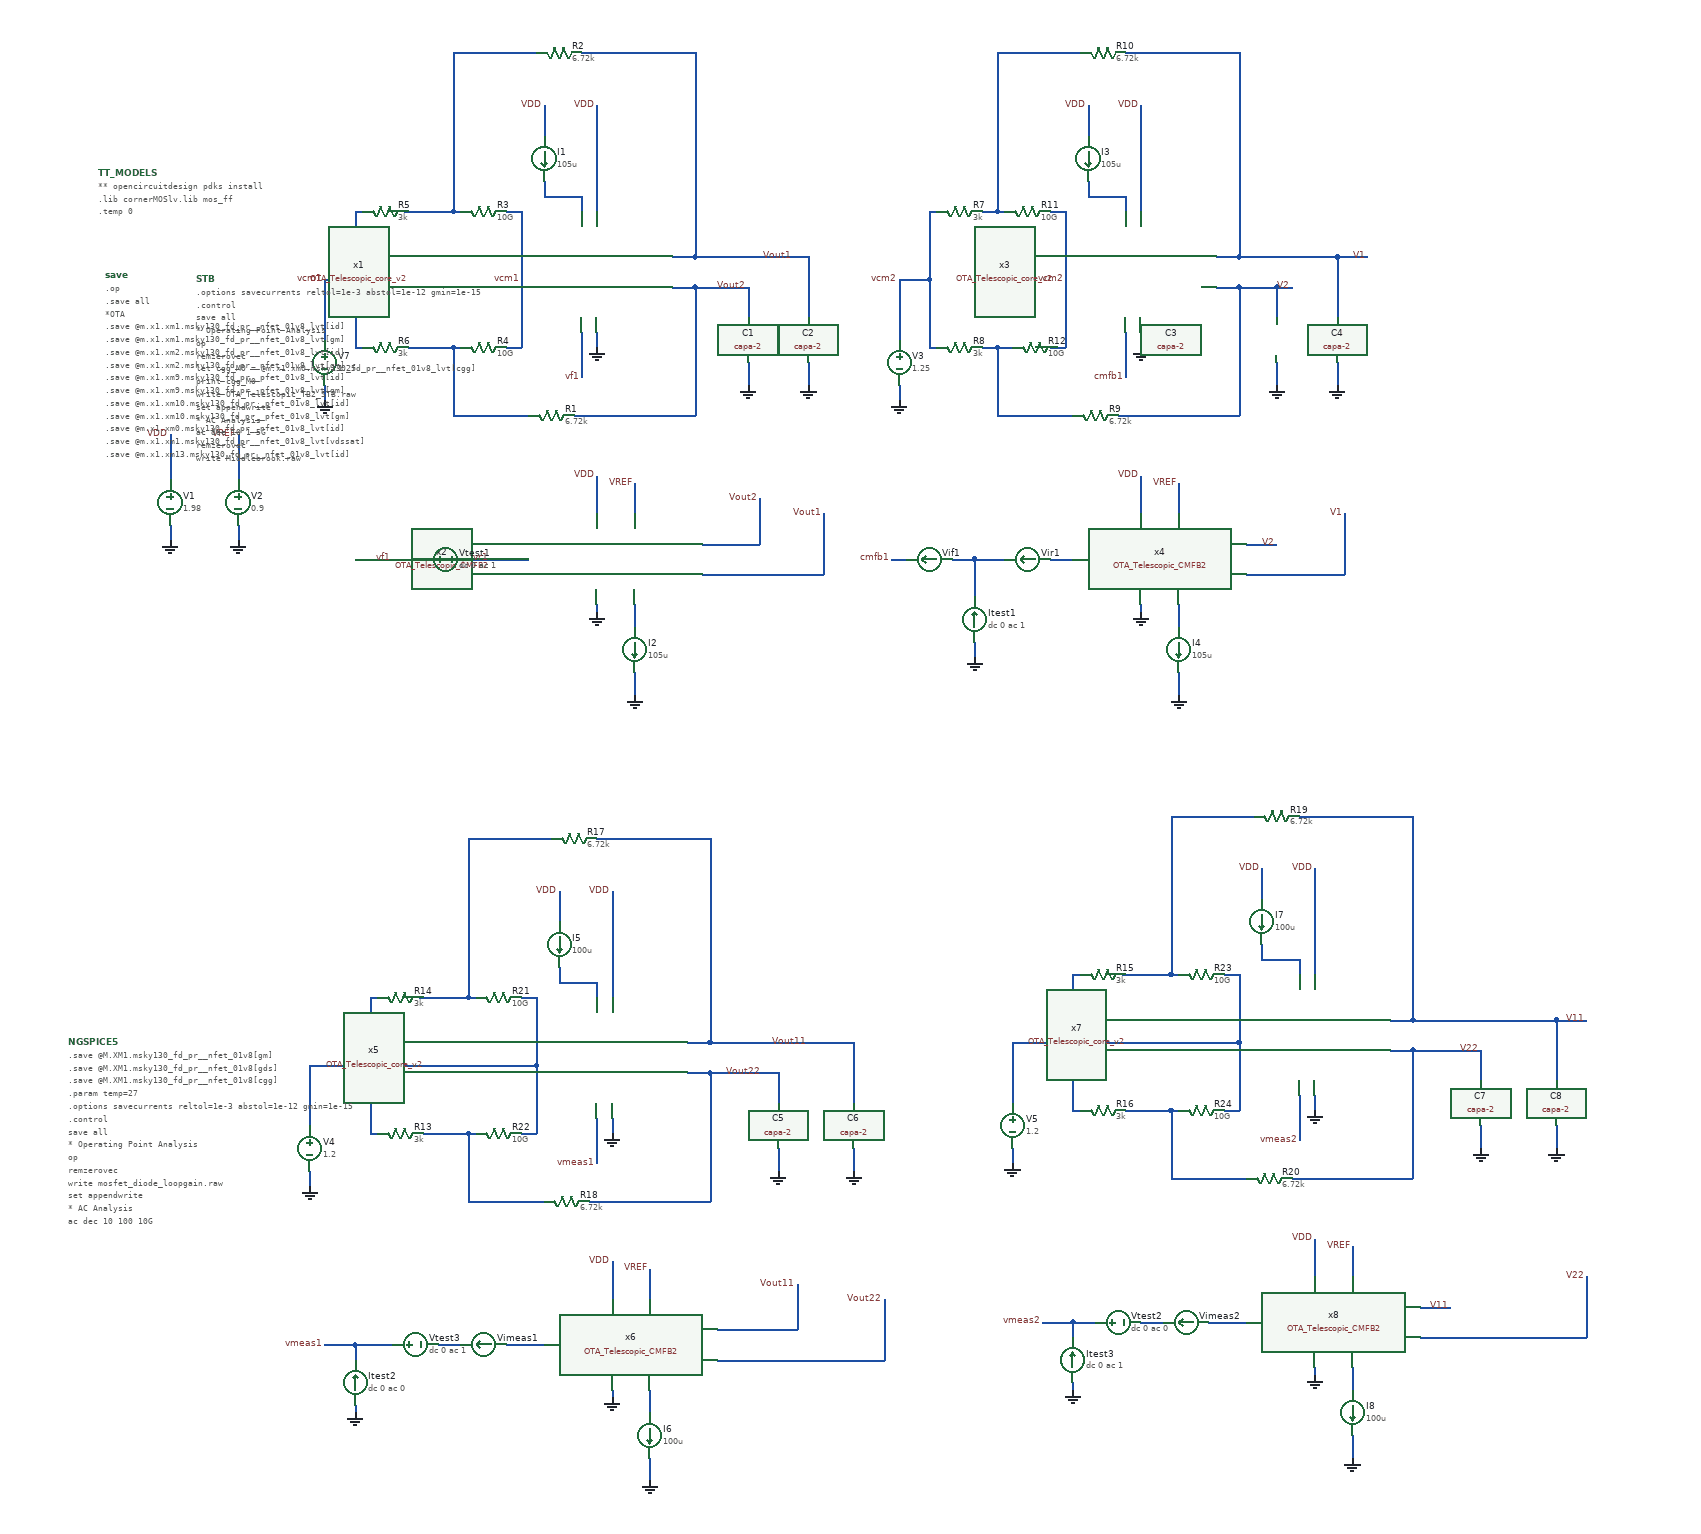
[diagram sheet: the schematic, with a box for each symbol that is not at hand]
v {xschem version=3.4.8RC file_version=1.2}
G {}
K {}
V {}
S {}
F {}
E {}
N 220 -440 370 -440 {lab=Vout1}
N -270 -410 -270 -330 {lab=vcm1}
N -270 -270 -270 -250 {lab=GND}
N 90 -340 90 -320 {lab=GND}
N -475 -85 -475 -65 {lab=GND}
N -475 -205 -475 -145 {lab=VDD}
N -385 -85 -385 -65 {lab=GND}
N -385 -205 -385 -145 {lab=VREF}
N 290 -400 290 -360 {lab=Vout2}
N 290 -300 290 -270 {lab=GND}
N 370 -300 370 -270 {lab=GND}
N 370 -440 370 -360 {lab=Vout1}
N -10 -500 -10 -320 {lab=vcm1}
N 70 -340 70 -280 {lab=vf1}
N 305 -120 305 -60 {lab=Vout2}
N -30 -500 -10 -500 {lab=vcm1}
N -30 -320 -10 -320 {lab=vcm1}
N -100 -500 -90 -500 {lab=#net1}
N -100 -320 -90 -320 {lab=#net2}
N 90 -640 90 -500 {lab=VDD}
N 20 -540 20 -520 {lab=#net3}
N 20 -520 70 -520 {lab=#net3}
N 70 -520 70 -500 {lab=#net3}
N 20 -640 20 -600 {lab=VDD}
N 190 -400 220 -400 {lab=Vout2}
N 140 -140 140 -100 {lab=VREF}
N 90 20 90 30 {lab=GND}
N 140 110 140 140 {lab=GND}
N 140 20 140 50 {lab=#net4}
N 90 -150 90 -100 {lab=VDD}
N -100 -710 10 -710 {lab=#net1}
N -100 -710 -100 -500 {lab=#net1}
N 70 -710 220 -710 {lab=Vout1}
N 220 -710 220 -440 {lab=Vout1}
N -100 -320 -100 -230 {lab=#net2}
N -100 -230 0 -230 {lab=#net2}
N 60 -230 220 -230 {lab=Vout2}
N 220 -400 220 -230 {lab=Vout2}
N 230 -20 390 -20 {lab=Vout1}
N -230 -320 -220 -320 {lab=vcm1}
N -230 -410 -230 -320 {lab=vcm1}
N -230 -500 -220 -500 {lab=vcm1}
N 390 -100 390 -20 {lab=Vout1}
N 490 -410 490 -330 {lab=vcm2}
N 490 -270 490 -250 {lab=GND}
N 810 -340 810 -320 {lab=GND}
N 990 -400 990 -360 {lab=V2}
N 990 -300 990 -270 {lab=GND}
N 1070 -300 1070 -270 {lab=GND}
N 1070 -440 1070 -360 {lab=V1}
N 710 -500 710 -320 {lab=vcm2}
N 790 -340 790 -280 {lab=cmfb1}
N 690 -500 710 -500 {lab=vcm2}
N 690 -320 710 -320 {lab=vcm2}
N 810 -640 810 -500 {lab=VDD}
N 740 -540 740 -520 {lab=#net5}
N 740 -520 790 -520 {lab=#net5}
N 790 -520 790 -500 {lab=#net5}
N 740 -640 740 -600 {lab=VDD}
N 910 -400 940 -400 {lab=V2}
N 860 -140 860 -100 {lab=VREF}
N 810 20 810 30 {lab=GND}
N 860 110 860 140 {lab=GND}
N 860 20 860 50 {lab=#net6}
N 810 -150 810 -100 {lab=VDD}
N 620 -710 730 -710 {lab=#net7}
N 620 -710 620 -500 {lab=#net7}
N 790 -710 940 -710 {lab=V1}
N 940 -710 940 -440 {lab=V1}
N 620 -320 620 -230 {lab=#net8}
N 620 -230 720 -230 {lab=#net8}
N 780 -230 940 -230 {lab=V2}
N 940 -400 940 -230 {lab=V2}
N 530 -320 540 -320 {lab=vcm2}
N 530 -410 530 -320 {lab=vcm2}
N 530 -500 540 -500 {lab=vcm2}
N 1080 -100 1080 -20 {lab=V1}
N 950 -60 990 -60 {lab=V2}
N 1070 -440 1110 -440 {lab=V1}
N 590 70 590 90 {lab=GND}
N 590 -40 590 10 {lab=#net9}
N 950 -20 1080 -20 {lab=V1}
N -230 -40 -140 -40 {lab=vf1}
N 480 -40 500 -40 {lab=cmfb1}
N 590 -40 630 -40 {lab=#net9}
N 240 600 430 600 {lab=Vout11}
N 240 640 330 640 {lab=Vout22}
N -290 630 -290 710 {lab=#net10}
N -290 770 -290 790 {lab=GND}
N 110 700 110 720 {lab=GND}
N 330 640 330 680 {lab=Vout22}
N 330 740 330 770 {lab=GND}
N 430 740 430 770 {lab=GND}
N 430 600 430 680 {lab=Vout11}
N 10 540 10 630 {lab=#net10}
N 90 700 90 760 {lab=vmeas1}
N 355 920 355 980 {lab=Vout11}
N -10 540 10 540 {lab=#net10}
N -10 720 10 720 {lab=#net10}
N -80 540 -70 540 {lab=#net11}
N -80 720 -70 720 {lab=#net12}
N 110 400 110 540 {lab=VDD}
N 40 500 40 520 {lab=#net13}
N 40 520 90 520 {lab=#net13}
N 90 520 90 540 {lab=#net13}
N 40 400 40 440 {lab=VDD}
N 210 640 240 640 {lab=Vout22}
N 160 900 160 940 {lab=VREF}
N 110 1060 110 1070 {lab=GND}
N 160 1150 160 1180 {lab=GND}
N 160 1060 160 1090 {lab=#net14}
N -30 1000 20 1000 {lab=#net15}
N 110 890 110 940 {lab=VDD}
N -80 330 30 330 {lab=#net11}
N -80 330 -80 540 {lab=#net11}
N 90 330 240 330 {lab=Vout11}
N 240 330 240 600 {lab=Vout11}
N -80 720 -80 810 {lab=#net12}
N -80 810 20 810 {lab=#net12}
N 80 810 240 810 {lab=Vout22}
N 240 640 240 810 {lab=Vout22}
N 250 1020 470 1020 {lab=Vout22}
N 250 980 355 980 {lab=Vout11}
N -210 720 -200 720 {lab=#net10}
N -210 630 -210 720 {lab=#net10}
N -210 540 -200 540 {lab=#net10}
N -290 630 -210 630 {lab=#net10}
N 10 630 10 720 {lab=#net10}
N 470 940 470 1020 {lab=Vout22}
N 1170 570 1360 570 {lab=V11}
N 1170 610 1260 610 {lab=V22}
N 640 600 640 680 {lab=#net16}
N 640 740 640 760 {lab=GND}
N 1040 670 1040 690 {lab=GND}
N 1260 610 1260 650 {lab=V22}
N 1260 710 1260 740 {lab=GND}
N 1360 710 1360 740 {lab=GND}
N 1360 570 1360 650 {lab=V11}
N 940 510 940 600 {lab=#net16}
N 1020 670 1020 730 {lab=vmeas2}
N 920 510 940 510 {lab=#net16}
N 920 690 940 690 {lab=#net16}
N 850 510 860 510 {lab=#net17}
N 850 690 860 690 {lab=#net18}
N 1040 370 1040 510 {lab=VDD}
N 970 470 970 490 {lab=#net19}
N 970 490 1020 490 {lab=#net19}
N 1020 490 1020 510 {lab=#net19}
N 970 370 970 410 {lab=VDD}
N 1140 610 1170 610 {lab=V22}
N 1090 870 1090 910 {lab=VREF}
N 1040 1030 1040 1040 {lab=GND}
N 1090 1120 1090 1150 {lab=GND}
N 1090 1030 1090 1060 {lab=#net20}
N 900 970 950 970 {lab=#net21}
N 1040 860 1040 910 {lab=VDD}
N 850 300 960 300 {lab=#net17}
N 850 300 850 510 {lab=#net17}
N 1020 300 1170 300 {lab=V11}
N 1170 300 1170 570 {lab=V11}
N 850 690 850 780 {lab=#net18}
N 850 780 950 780 {lab=#net18}
N 1010 780 1170 780 {lab=V22}
N 1170 610 1170 780 {lab=V22}
N 720 690 730 690 {lab=#net16}
N 720 600 720 690 {lab=#net16}
N 720 510 730 510 {lab=#net16}
N 640 600 720 600 {lab=#net16}
N 940 600 940 690 {lab=#net16}
N 1400 910 1400 990 {lab=V22}
N 1180 950 1220 950 {lab=V11}
N 1360 570 1400 570 {lab=V11}
N 1180 990 1400 990 {lab=V22}
N -230 1000 -180 1000 {lab=vmeas1}
N 720 970 750 970 {lab=vmeas2}
N -210 630 10 630 {lab=#net10}
N 720 600 940 600 {lab=#net16}
N -120 1000 -90 1000 {lab=#net22}
N 810 970 840 970 {lab=#net23}
N -230 1000 -230 1020 {lab=vmeas1}
N -230 1080 -230 1090 {lab=GND}
N 720 1050 720 1060 {lab=GND}
N 720 970 720 990 {lab=vmeas2}
N -80 -40 0 -40 {lab=vr1}
N 690 -40 720 -40 {lab=#net24}
N 490 -410 530 -410 {lab=vcm2}
N -270 -410 -230 -410 {lab=vcm1}
N 620 -500 630 -500 {lab=#net7}
N 620 -320 640 -320 {lab=#net8}
N 990 -400 1010 -400 {lab=V2}
N 940 -440 1070 -440 {lab=V1}
N 230 -60 305 -60 {lab=Vout2}
N 220 -400 290 -400 {lab=Vout2}
N -165 -500 -100 -500 {lab=#net1}
N 190 -440 220 -440 {lab=Vout1}
N -160 -320 -100 -320 {lab=#net2}
N 940 -400 990 -400 {lab=V2}
N 600 -500 620 -500 {lab=#net7}
N 910 -440 940 -440 {lab=V1}
N 600 -320 620 -320 {lab=#net8}
N 560 -40 590 -40 {lab=#net9}
N -145 540 -80 540 {lab=#net11}
N 210 600 240 600 {lab=Vout11}
N -140 720 -80 720 {lab=#net12}
N -210 540 -210 630 {lab=#net10}
N 785 510 850 510 {lab=#net17}
N 1140 570 1170 570 {lab=V11}
N 790 690 850 690 {lab=#net18}
N 720 510 720 600 {lab=#net16}
N -270 1000 -230 1000 {lab=vmeas1}
N 680 970 720 970 {lab=vmeas2}
N 530 -500 530 -410 {lab=vcm2}
N -230 -500 -230 -410 {lab=vcm1}
C {vsource.sym} -270 -300 0 0 {name=V7 value=1.25 savecurrent=false}
C {gnd.sym} -270 -250 0 0 {name=l5 lab=GND}
C {gnd.sym} 90 -320 0 0 {name=l2 lab=GND}
C {vsource.sym} -475 -115 0 0 {name=V1 value=1.98 savecurrent=false}
C {gnd.sym} -475 -65 0 0 {name=l3 lab=GND}
C {lab_wire.sym} -475 -205 0 0 {name=p1 sig_type=std_logic lab=VDD}
C {vsource.sym} -385 -115 0 0 {name=V2 value=0.9 savecurrent=false}
C {gnd.sym} -385 -65 0 0 {name=l4 lab=GND}
C {lab_wire.sym} -385 -205 0 0 {name=p4 sig_type=std_logic lab=VREF}
C {capa-2.sym} 290 -330 0 0 {name=C1
m=1
value=500f
footprint=1206
device=polarized_capacitor}
C {gnd.sym} 290 -270 0 0 {name=l10 lab=GND}
C {capa-2.sym} 370 -330 0 0 {name=C2
m=1
value=500f
footprint=1206
device=polarized_capacitor}
C {gnd.sym} 370 -270 0 0 {name=l7 lab=GND}
C {lab_wire.sym} 290 -400 0 0 {name=p19 sig_type=std_logic lab=Vout2}
C {lab_wire.sym} 350 -440 0 0 {name=p18 sig_type=std_logic lab=Vout1}
C {devices/code.sym} -570 -550.390625 0 0 {name=TT_MODELS
only_toplevel=true
format="tcleval( @value )"
value="
** opencircuitdesign pdks install
.lib cornerMOSlv.lib mos_ff
.temp 0
"
}
C {devices/launcher.sym} -430 -630 0 0 {name=h3
descr="save, netlist & simulate"
tclcommand="xschem save; xschem netlist; xschem simulate"
value="
.param wx=5u lx=0.13u vbx=0
.save all
.save @n.xm1.nsg13_lv_nmos[gm]
.save @n.xm1.nsg13_lv_nmos[ids]
.save @n.xm1.nsg13_lv_nmos[sid]
.save @n.xm1.nsg13_lv_nmos[sfl]

.control
set wr_vecnames
op
noise v(n) vg dec 10 1 1e11 1
noise v(n) vg lin  1 1 1 1
echo $plots
write noisetest_sg13g2_lv_nmos.raw noise1.all

setplot noise3
print onoise_spectrum
print onoise_n.xm1.nsg13_lv_nmos_flicker
print onoise_n.xm1.nsg13_lv_nmos_idid
print sqrt(@n.xm1.nsg13_lv_nmos[sfl])
print sqrt(@n.xm1.nsg13_lv_nmos[sid])
.endc
"}
C {code.sym} -560 -415 0 0 {name=save only_toplevel=false value="
.op

.save all
*OTA
.save @m.x1.xm1.msky130_fd_pr__nfet_01v8_lvt[id]
.save @m.x1.xm1.msky130_fd_pr__nfet_01v8_lvt[gm]
.save @m.x1.xm2.msky130_fd_pr__nfet_01v8_lvt[id]
.save @m.x1.xm2.msky130_fd_pr__nfet_01v8_lvt[gm]

.save @m.x1.xm9.msky130_fd_pr__pfet_01v8_lvt[id]
.save @m.x1.xm9.msky130_fd_pr__pfet_01v8_lvt[gm]
.save @m.x1.xm10.msky130_fd_pr__pfet_01v8_lvt[id]
.save @m.x1.xm10.msky130_fd_pr__pfet_01v8_lvt[gm]

.save @m.x1.xm0.msky130_fd_pr__nfet_01v8_lvt[id]

.save @m.x1.xm1.msky130_fd_pr__nfet_01v8_lvt[vdssat]


.save @m.x1.xm13.msky130_fd_pr__nfet_01v8_lvt[id]
.save @m.x1.xm14.msky130_fd_pr__nfet_01v8_lvt[id]
.save @m.x1.xm15.msky130_fd_pr__pfet_01v8_lvt[id]
.save @m.x1.xm16.msky130_fd_pr__nfet_01v8_lvt[id]
.save @m.x1.xm17.msky130_fd_pr__nfet_01v8_lvt[id]

.save @m.x1.xm18.msky130_fd_pr__pfet_01v8_lvt[id]
.save @m.x1.xm19.msky130_fd_pr__nfet_01v8_lvt[id]

*CMFB
.save @m.x2.xm0.msky130_fd_pr__pfet_01v8_lvt[id]
.save @m.x2.xm1.msky130_fd_pr__pfet_01v8_lvt[id]
.save @m.x2.xm1.msky130_fd_pr__pfet_01v8_lvt[gm]
.save @m.x2.xm2.msky130_fd_pr__pfet_01v8_lvt[id]
.save @m.x2.xm2.msky130_fd_pr__pfet_01v8_lvt[gm]
.save @m.x2.xm3.msky130_fd_pr__pfet_01v8_lvt[id]
.save @m.x2.xm3.msky130_fd_pr__pfet_01v8_lvt[gm]
.save @m.x2.xm4.msky130_fd_pr__pfet_01v8_lvt[id]
.save @m.x2.xm4.msky130_fd_pr__pfet_01v8_lvt[gm]
.save @m.x2.xm5.msky130_fd_pr__pfet_01v8_lvt[id]
.save @m.x2.xm5.msky130_fd_pr__pfet_01v8_lvt[gm]
.save @m.x2.xm6.msky130_fd_pr__pfet_01v8_lvt[id]
.save @m.x2.xm6.msky130_fd_pr__pfet_01v8_lvt[gm]

.save @m.x2.xm7.msky130_fd_pr__nfet_01v8_lvt[id]
.save @m.x2.xm7.msky130_fd_pr__nfet_01v8_lvt[gm]
.save @m.x2.xm8.msky130_fd_pr__nfet_01v8_lvt[id]
.save @m.x2.xm8.msky130_fd_pr__nfet_01v8_lvt[gm]



.control

let vdssat_M1 = @m.x1.xm1.msky130_fd_pr__nfet_01v8_lvt[vdsat]
let vdssat_M3 = @m.x1.xm3.msky130_fd_pr__nfet_01v8_lvt[vdsat]
let vdssat_M5 = @m.x1.xm5.msky130_fd_pr__pfet_01v8_lvt[vdsat]
let vdssat_M7 = @m.x1.xm7.msky130_fd_pr__pfet_01v8_lvt[vdsat]
let vdssat_M0 = @m.x1.xm0.msky130_fd_pr__nfet_01v8_lvt[vdsat]

let vdssat_M9 = @m.x1.xm9.msky130_fd_pr__pfet_01v8_lvt[vdsat]
let vdssat_M11 = @m.x1.xm11.msky130_fd_pr__nfet_01v8_lvt[vdsat]

print vdssat_M1
print vdssat_M3
print vdssat_M5
print vdssat_M7
print vdssat_M0
print vdssat_M9
print vdssat_M11

let ro_M1 = 1/@m.x1.xm1.msky130_fd_pr__nfet_01v8_lvt[gds]
let ro_M3 = 1/@m.x1.xm3.msky130_fd_pr__nfet_01v8_lvt[gds]
let ro_M5 = 1/@m.x1.xm5.msky130_fd_pr__pfet_01v8_lvt[gds]
let ro_M7 = 1/@m.x1.xm7.msky130_fd_pr__pfet_01v8_lvt[gds]
let ro_M0 = 1/@m.x1.xm0.msky130_fd_pr__nfet_01v8_lvt[gds]

print ro_M1
print ro_M3
print ro_M5
print ro_M7
print ro_M0

let gm_M1 = @m.x1.xm1.msky130_fd_pr__nfet_01v8_lvt[gm]
let gm_M3 = @m.x1.xm3.msky130_fd_pr__nfet_01v8_lvt[gm]
let gm_M5 = @m.x1.xm5.msky130_fd_pr__pfet_01v8_lvt[gm]
let gm_M7 = @m.x1.xm7.msky130_fd_pr__pfet_01v8_lvt[gm]
let gm_M0 = @m.x1.xm0.msky130_fd_pr__nfet_01v8_lvt[gm]

print gm_M1
print gm_M3
print gm_M5
print gm_M7
print gm_M0

let gmb_M3 = @m.x1.xm3.msky130_fd_pr__nfet_01v8_lvt[gmbs]
let gmb_M5 = @m.x1.xm5.msky130_fd_pr__pfet_01v8_lvt[gmbs]

print gmb_M3
print gmb_M5


let cgg_M0 = @m.x1.xm0.msky130_fd_pr__nfet_01v8_lvt[cgg]
print cgg_M0


*CMFB

let x2_vdssat_M0 = @m.x2.xm0.msky130_fd_pr__pfet_01v8_lvt[vdsat]
let x2_vth_M0 = @m.x2.xm0.msky130_fd_pr__pfet_01v8_lvt[vth]

print x2_vdssat_M0
print x2_vth_M0

.endc

"
}
C {lab_wire.sym} 305 -120 0 0 {name=p9 sig_type=std_logic lab=Vout2}
C {res.sym} -190 -500 1 0 {name=R5
value=3k
footprint=1206
device=resistor
m=1
}
C {res.sym} -190 -320 1 0 {name=R6
value=3k
footprint=1206
device=resistor
m=1}
C {lab_wire.sym} 20 -640 0 0 {name=p2 sig_type=std_logic lab=VDD}
C {lab_wire.sym} 90 -640 0 0 {name=p10 sig_type=std_logic lab=VDD}
C {isource.sym} 20 -570 0 0 {name=I1 value=105u}
C {OTA_Telescopic_core_v2.sym} 70 -420 0 0 {name=x1}
C {OTA_Telescopic_CMFB2.sym} 150 -40 0 1 {name=x2}
C {gnd.sym} 90 30 0 0 {name=l1 lab=GND}
C {isource.sym} 140 80 0 0 {name=I2 value=105u}
C {gnd.sym} 140 140 0 0 {name=l6 lab=GND}
C {lab_wire.sym} 90 -150 0 0 {name=p5 sig_type=std_logic lab=VDD}
C {lab_wire.sym} 390 -100 0 0 {name=p11 sig_type=std_logic lab=Vout1}
C {res.sym} 30 -230 1 0 {name=R1
value=6.72k
footprint=1206
device=resistor
m=1}
C {res.sym} 40 -710 1 0 {name=R2
value=6.72k
footprint=1206
device=resistor
m=1}
C {devices/vsource.sym} -110 -40 1 0 {name=Vtest1 value="dc 0 ac 1"}
C {vsource.sym} 490 -300 0 0 {name=V3 value=1.25 savecurrent=false}
C {gnd.sym} 490 -250 0 0 {name=l15 lab=GND}
C {gnd.sym} 810 -320 0 0 {name=l16 lab=GND}
C {capa-2.sym} 990 -330 0 0 {name=C3
m=1
value=500f
footprint=1206
device=polarized_capacitor}
C {gnd.sym} 990 -270 0 0 {name=l17 lab=GND}
C {capa-2.sym} 1070 -330 0 0 {name=C4
m=1
value=500f
footprint=1206
device=polarized_capacitor}
C {gnd.sym} 1070 -270 0 0 {name=l18 lab=GND}
C {res.sym} 570 -500 1 0 {name=R7
value=3k
footprint=1206
device=resistor
m=1
}
C {res.sym} 570 -320 1 0 {name=R8
value=3k
footprint=1206
device=resistor
m=1}
C {lab_wire.sym} 790 -280 0 0 {name=p17 sig_type=std_logic lab=cmfb1}
C {lab_wire.sym} 740 -640 0 0 {name=p20 sig_type=std_logic lab=VDD}
C {lab_wire.sym} 810 -640 0 0 {name=p21 sig_type=std_logic lab=VDD}
C {isource.sym} 740 -570 0 0 {name=I3 value=105u}
C {OTA_Telescopic_core_v2.sym} 790 -420 0 0 {name=x3}
C {OTA_Telescopic_CMFB2.sym} 870 -40 0 1 {name=x4}
C {gnd.sym} 810 30 0 0 {name=l19 lab=GND}
C {isource.sym} 860 80 0 0 {name=I4 value=105u}
C {gnd.sym} 860 140 0 0 {name=l20 lab=GND}
C {lab_wire.sym} 480 -40 0 0 {name=p22 sig_type=std_logic lab=cmfb1}
C {lab_wire.sym} 810 -150 0 0 {name=p23 sig_type=std_logic lab=VDD}
C {res.sym} 750 -230 1 0 {name=R9
value=6.72k
footprint=1206
device=resistor
m=1}
C {res.sym} 760 -710 1 0 {name=R10
value=6.72k
footprint=1206
device=resistor
m=1}
C {lab_wire.sym} 140 -140 0 0 {name=p6 sig_type=std_logic lab=VREF}
C {lab_wire.sym} 860 -140 0 0 {name=p15 sig_type=std_logic lab=VREF}
C {ammeter.sym} 530 -40 1 0 {name=Vif1 savecurrent=true spice_ignore=0}
C {ammeter.sym} 660 -40 1 0 {name=Vir1 savecurrent=true spice_ignore=0}
C {isource.sym} 590 40 2 0 {name=Itest1 value="dc 0 ac 1"}
C {devices/gnd.sym} 590 90 0 0 {name=l21 lab=GND}
C {code.sym} -440 -410 0 0 {name=STB
only_toplevel=true
value="

.options savecurrents reltol=1e-3 abstol=1e-12 gmin=1e-15
.control
save all

* Operating Point Analysis
op
remzerovec
let cgg_M0 = @m.x1.xm0.msky130_fd_pr__nfet_01v8_lvt[cgg]
print cgg_M0
write OTA_Telescopic_TB2_STB.raw
set appendwrite

* AC Analysis
ac dec 10 1 5G
remzerovec
write Middlebrook.raw
set appendwrite

* Middlebrook's Method
let tv=-v(vr1)/v(vf1)
let ti=-i(vir1)/i(vif1)
let tmb=(tv*ti - 1)/(tv + ti + 2)

let Av = db(tmb)
meas ac Ao MAX Av
let ABW = Ao-3
meas ac BW WHEN Av=ABW
meas ac UGBW WHEN Av=0

* Phase margin (PM)
let phase_vec= 180/pi*cph(tmb)
meas ac phase FIND phase_vec WHEN frequency=UGBW
let PM = phase+180
print PM

* Gain margin (GM)
meas ac freq180 FIND frequency WHEN phase_vec=-180
meas ac gain FIND Av WHEN frequency=freq180
let GM = 0-gain
print GM

plot Av ylabel 'Magnitude - Middlebrook'
plot phase_vec ylabel 'Phase - Middlebrook'

write Middlebrook_.raw

wrdata STB_Av_ Av
wrdata STB_ph_ phase_vec

*quit

.endc
"
}
C {lab_wire.sym} 1110 -440 0 0 {name=p7 sig_type=std_logic lab=V1}
C {lab_wire.sym} 1010 -400 0 0 {name=p8 sig_type=std_logic lab=V2}
C {lab_wire.sym} -50 -40 0 0 {name=p13 sig_type=std_logic lab=vr1}
C {lab_wire.sym} -180 -40 0 0 {name=p12 sig_type=std_logic lab=vf1}
C {lab_wire.sym} 70 -280 0 0 {name=p3 sig_type=std_logic lab=vf1}
C {lab_wire.sym} 990 -60 0 0 {name=p14 sig_type=std_logic lab=V2}
C {lab_wire.sym} 1080 -100 0 0 {name=p16 sig_type=std_logic lab=V1}
C {vsource.sym} -290 740 0 0 {name=V4 value=1.2 savecurrent=false}
C {gnd.sym} -290 790 0 0 {name=l8 lab=GND}
C {gnd.sym} 110 720 0 0 {name=l9 lab=GND}
C {capa-2.sym} 330 710 0 0 {name=C5
m=1
value=500f
footprint=1206
device=polarized_capacitor}
C {gnd.sym} 330 770 0 0 {name=l11 lab=GND}
C {capa-2.sym} 430 710 0 0 {name=C6
m=1
value=500f
footprint=1206
device=polarized_capacitor}
C {gnd.sym} 430 770 0 0 {name=l12 lab=GND}
C {lab_wire.sym} 310 640 0 0 {name=p24 sig_type=std_logic lab=Vout22}
C {lab_wire.sym} 370 600 0 0 {name=p25 sig_type=std_logic lab=Vout11}
C {lab_wire.sym} 355 920 0 0 {name=p26 sig_type=std_logic lab=Vout11}
C {lab_wire.sym} 40 400 0 0 {name=p27 sig_type=std_logic lab=VDD}
C {lab_wire.sym} 110 400 0 0 {name=p28 sig_type=std_logic lab=VDD}
C {isource.sym} 40 470 0 0 {name=I5 value=100u}
C {OTA_Telescopic_core_v2.sym} 90 620 0 0 {name=x5}
C {OTA_Telescopic_CMFB2.sym} 170 1000 0 1 {name=x6}
C {gnd.sym} 110 1070 0 0 {name=l13 lab=GND}
C {isource.sym} 160 1120 0 0 {name=I6 value=100u}
C {gnd.sym} 160 1180 0 0 {name=l14 lab=GND}
C {lab_wire.sym} 110 890 0 0 {name=p29 sig_type=std_logic lab=VDD}
C {lab_wire.sym} 470 940 0 0 {name=p30 sig_type=std_logic lab=Vout22}
C {vsource.sym} 640 710 0 0 {name=V5 value=1.2 savecurrent=false}
C {gnd.sym} 640 760 0 0 {name=l22 lab=GND}
C {gnd.sym} 1040 690 0 0 {name=l23 lab=GND}
C {capa-2.sym} 1260 680 0 0 {name=C7
m=1
value=500f
footprint=1206
device=polarized_capacitor}
C {gnd.sym} 1260 740 0 0 {name=l24 lab=GND}
C {capa-2.sym} 1360 680 0 0 {name=C8
m=1
value=500f
footprint=1206
device=polarized_capacitor}
C {gnd.sym} 1360 740 0 0 {name=l25 lab=GND}
C {lab_wire.sym} 970 370 0 0 {name=p32 sig_type=std_logic lab=VDD}
C {lab_wire.sym} 1040 370 0 0 {name=p33 sig_type=std_logic lab=VDD}
C {isource.sym} 970 440 0 0 {name=I7 value=100u}
C {OTA_Telescopic_core_v2.sym} 1020 590 0 0 {name=x7}
C {OTA_Telescopic_CMFB2.sym} 1100 970 0 1 {name=x8}
C {gnd.sym} 1040 1040 0 0 {name=l26 lab=GND}
C {isource.sym} 1090 1090 0 0 {name=I8 value=100u}
C {gnd.sym} 1090 1150 0 0 {name=l27 lab=GND}
C {lab_wire.sym} 1040 860 0 0 {name=p35 sig_type=std_logic lab=VDD}
C {lab_wire.sym} 160 900 0 0 {name=p36 sig_type=std_logic lab=VREF}
C {lab_wire.sym} 1090 870 0 0 {name=p37 sig_type=std_logic lab=VREF}
C {lab_wire.sym} 1400 570 0 0 {name=p38 sig_type=std_logic lab=V11}
C {lab_wire.sym} 1260 610 0 0 {name=p39 sig_type=std_logic lab=V22}
C {res.sym} -40 540 1 0 {name=R21
value=10G
footprint=1206
device=resistor
m=1
}
C {res.sym} -40 720 1 0 {name=R22
value=10G
footprint=1206
device=resistor
m=1
}
C {res.sym} 890 510 1 0 {name=R23
value=10G
footprint=1206
device=resistor
m=1
}
C {res.sym} 890 690 1 0 {name=R24
value=10G
footprint=1206
device=resistor
m=1
}
C {lab_wire.sym} 1220 950 0 0 {name=p43 sig_type=std_logic lab=V11}
C {lab_wire.sym} 1400 910 0 0 {name=p44 sig_type=std_logic lab=V22}
C {code.sym} -610 600 0 0 {name=NGSPICE5
only_toplevel=true
value="
.save @M.XM1.msky130_fd_pr__nfet_01v8[gm] 
.save @M.XM1.msky130_fd_pr__nfet_01v8[gds] 
.save @M.XM1.msky130_fd_pr__nfet_01v8[cgg] 
.param temp=27
.options savecurrents reltol=1e-3 abstol=1e-12 gmin=1e-15
.control
save all

* Operating Point Analysis
op
remzerovec
write mosfet_diode_loopgain.raw
set appendwrite

* AC Analysis
ac dec 10 100 10G
remzerovec
write mosfet_diode_loopgain.raw
set appendwrite

* Tian's Method
* vtest=0, itest=1:
let A=i(Vimeas2)
let C=v(vmeas2)

* vtest=1, itest=0:
let B=i(Vimeas1)
let D=v(vmeas1)
let ttian=(A*D-B*C-A)/(2*(B*C-A*D)+A-D+1)

plot db(ttian) ylabel 'Magnitude - Tian'
plot 180/pi*cphase(ttian) ylabel 'Phase - Tian'

write mosfet_diode_loopgain.raw

let Av_tian = db(ttian)
meas ac Ao_tian MAX Av_tian
let ABW_tian = Ao_tian-3
meas ac BW_tian WHEN Av_tian=ABW_tian
meas ac UGBW_tian WHEN Av_tian=0

* Phase margin (PM)
let phase_vec=180/pi*cphase(ttian)
meas ac phase FIND phase_vec WHEN frequency=UGBW_tian 
let PM = phase+180
print PM

* Gain margin (GM)
*meas ac freq180 FIND frequency WHEN phase_vec=-180
*meas ac gain FIND Av WHEN frequency=freq180
*let GM = 0-gain
*print GM


*quit
op
print 1/@M.XM1.msky130_fd_pr__nfet_01v8[gds]
print @M.XM1.msky130_fd_pr__nfet_01v8[cgg]  
print @M.XM1.msky130_fd_pr__nfet_01v8[cgs]+@M.XM1.msky130_fd_pr__nfet_01v8[cdb]+@M.XM1.msky130_fd_pr__nfet_01v8[cgb]
.endc
"
spice_ignore=true}
C {devices/vsource.sym} -150 1000 3 0 {name=Vtest3 value="dc 0 ac 1"}
C {ammeter.sym} -60 1000 1 0 {name=Vimeas1 savecurrent=true spice_ignore=0}
C {lab_wire.sym} -270 1000 0 0 {name=p45 sig_type=std_logic lab=vmeas1}
C {lab_wire.sym} 90 760 0 0 {name=p41 sig_type=std_logic lab=vmeas1}
C {devices/vsource.sym} 780 970 3 0 {name=Vtest2 value="dc 0 ac 0"}
C {ammeter.sym} 870 970 1 0 {name=Vimeas2 savecurrent=true spice_ignore=0}
C {lab_wire.sym} 680 970 0 0 {name=p42 sig_type=std_logic lab=vmeas2}
C {lab_wire.sym} 1020 730 0 0 {name=p31 sig_type=std_logic lab=vmeas2}
C {isource.sym} -230 1050 2 0 {name=Itest2 value="dc 0 ac 0"}
C {devices/gnd.sym} -230 1090 0 0 {name=l28 lab=GND}
C {isource.sym} 720 1020 2 0 {name=Itest3 value="dc 0 ac 1"}
C {devices/gnd.sym} 720 1060 0 0 {name=l29 lab=GND}
C {res.sym} -60 -500 1 0 {name=R3
value=10G
footprint=1206
device=resistor
m=1
}
C {res.sym} -60 -320 1 0 {name=R4
value=10G
footprint=1206
device=resistor
m=1
}
C {res.sym} 660 -500 1 0 {name=R11
value=10G
footprint=1206
device=resistor
m=1
}
C {res.sym} 670 -320 1 0 {name=R12
value=10G
footprint=1206
device=resistor
m=1
}
C {res.sym} -170 720 1 0 {name=R13
value=3k
footprint=1206
device=resistor
m=1}
C {res.sym} -170 540 1 0 {name=R14
value=3k
footprint=1206
device=resistor
m=1}
C {res.sym} 760 510 1 0 {name=R15
value=3k
footprint=1206
device=resistor
m=1}
C {res.sym} 760 690 1 0 {name=R16
value=3k
footprint=1206
device=resistor
m=1}
C {res.sym} 60 330 1 0 {name=R17
value=6.72k
footprint=1206
device=resistor
m=1}
C {res.sym} 50 810 1 0 {name=R18
value=6.72k
footprint=1206
device=resistor
m=1}
C {res.sym} 990 300 1 0 {name=R19
value=6.72k
footprint=1206
device=resistor
m=1}
C {res.sym} 980 780 1 0 {name=R20
value=6.72k
footprint=1206
device=resistor
m=1}
C {lab_wire.sym} -270 -410 0 0 {name=p34 sig_type=std_logic lab=vcm1}
C {lab_wire.sym} -10 -410 0 0 {name=p40 sig_type=std_logic lab=vcm1}
C {lab_wire.sym} 490 -410 0 0 {name=p46 sig_type=std_logic lab=vcm2}
C {lab_wire.sym} 710 -410 0 0 {name=p47 sig_type=std_logic lab=vcm2}
